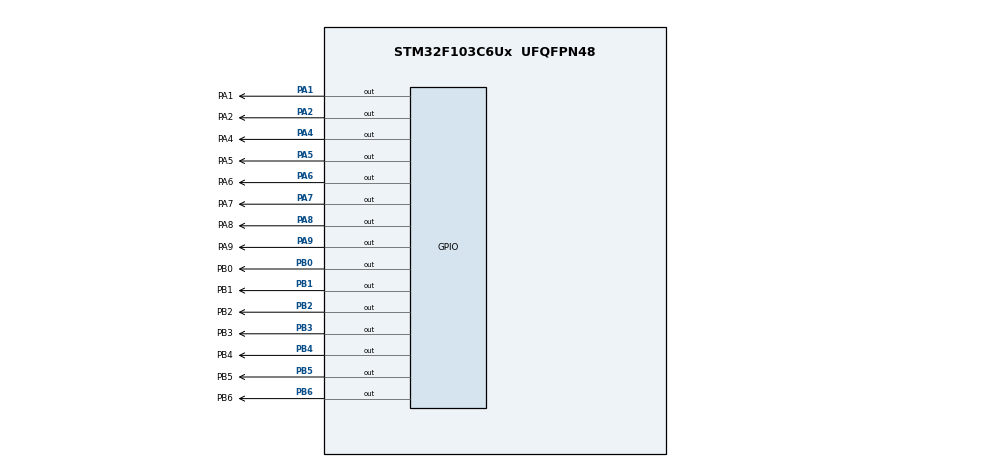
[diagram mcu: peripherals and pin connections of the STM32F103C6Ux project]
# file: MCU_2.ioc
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Mcu.Family=STM32F1
Mcu.Name=STM32F103C6Ux
Mcu.Package=UFQFPN48
NVIC.PriorityGroup=NVIC_PRIORITYGROUP_4
NVIC.TIM2_IRQn=true\:0\:0\:false\:false\:true\:true\:true\:true
PA1.GPIO_Label=PA1
PA1.Signal=GPIO_Output
PA13.Mode=Serial_Wire
PA13.Signal=SYS_JTMS-SWDIO
PA14.Mode=Serial_Wire
PA14.Signal=SYS_JTCK-SWCLK
PA2.GPIO_Label=PA2
PA2.Signal=GPIO_Output
PA4.GPIO_Label=PA4
PA4.Signal=GPIO_Output
PA5.GPIO_Label=PA5
PA5.Signal=GPIO_Output
PA6.GPIO_Label=PA6
PA6.Signal=GPIO_Output
PA7.GPIO_Label=PA7
PA7.Signal=GPIO_Output
PA8.GPIO_Label=PA8
PA8.Signal=GPIO_Output
PA9.GPIO_Label=PA9
PA9.Signal=GPIO_Output
PB0.GPIO_Label=PB0
PB0.Signal=GPIO_Output
PB1.GPIO_Label=PB1
PB1.Signal=GPIO_Output
PB2.GPIO_Label=PB2
PB2.Signal=GPIO_Output
PB3.GPIO_Label=PB3
PB3.Signal=GPIO_Output
PB4.GPIO_Label=PB4
PB4.Signal=GPIO_Output
PB5.GPIO_Label=PB5
PB5.Signal=GPIO_Output
PB6.GPIO_Label=PB6
PB6.Signal=GPIO_Output
ProjectManager.HeapSize=0x200
ProjectManager.StackSize=0x400
ProjectManager.TargetToolchain=STM32CubeIDE
RCC.APB1Freq_Value=8000000
RCC.APB2Freq_Value=8000000
TIM2.Period=9
TIM2.Prescaler=7999
VP_TIM2_VS_ClockSourceINT.Mode=Internal
board=custom

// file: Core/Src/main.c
/* USER CODE BEGIN Header */
/**
  ******************************************************************************
  * @file           : main.c
  * @brief          : Main program body
  ******************************************************************************
  * @attention
  *
  * Copyright (c) 2023 STMicroelectronics.
  * All rights reserved.
  *
  * This software is licensed under terms that can be found in the LICENSE file
  * in the root directory of this software component.
  * If no LICENSE file comes with this software, it is provided AS-IS.
  *
  ******************************************************************************
  */
/* USER CODE END Header */
#include "main.h"

/* USER CODE BEGIN Includes */
#include "software_timer.h"

/* USER CODE END Includes */

TIM_HandleTypeDef htim2;

void SystemClock_Config(void);
static void MX_GPIO_Init(void);
static void MX_TIM2_Init(void);

/* USER CODE BEGIN 0 */
void Ex_Init(){
	HAL_GPIO_WritePin(GPIOA, PA1_Pin|PA2_Pin|PA3_Pin| PA4_Pin|PA5_Pin| PA6_Pin, SET);
    HAL_GPIO_WritePin(GPIOB, PB8_Pin|PB9_Pin|PB10_Pin|PB11_Pin|PB12_Pin|PB13_Pin|PB14_Pin|PB15_Pin, SET);
    HAL_GPIO_WritePin(GPIOA, PA8_Pin|PA9_Pin|PA10_Pin|PA11_Pin|PA12_Pin|PA13_Pin|PA14_Pin|PA15_Pin, SET);
}

uint16_t row_pin[8] = {PB8_Pin,PB9_Pin,PB10_Pin,PB11_Pin,PB12_Pin,PB13_Pin,PB14_Pin,PB15_Pin};
uint16_t col_pin[8] = {PA8_Pin,PA9_Pin,PA10_Pin,PA11_Pin,PA12_Pin,PA13_Pin,PA14_Pin,PA15_Pin};
const int MAX_LED_MATRIX = 8;
int index_led_matrix = 0;
uint8_t matrix_buffer[8] = {0x1F, 0x24, 0x44, 0xC4, 0xC4, 0x44, 0x24, 0x1F};

void updateLEDMatrix(int index) {
	HAL_GPIO_WritePin(GPIOB, PB8_Pin|PB9_Pin|PB10_Pin|PB11_Pin|PB12_Pin|PB13_Pin|PB14_Pin|PB15_Pin, SET);
	HAL_GPIO_WritePin(GPIOA, PA8_Pin|PA9_Pin|PA10_Pin|PA11_Pin|PA12_Pin|PA13_Pin|PA14_Pin|PA15_Pin, SET);
	for(int j = 0; j < 100; j++){
		for(int i = 0; i < 8; i++) {
			if(matrix_buffer[index] & (0x01 << i)) {
				HAL_GPIO_WritePin(GPIOB, row_pin[i], RESET);
			}
		}

		HAL_GPIO_WritePin(GPIOA, col_pin[index], RESET);
	}

}

void display7SEG(int num){
  	uint8_t signal[10] = {0xC0, 0xF9, 0xA4, 0xB0, 0x99, 0x12, 0x82, 0xF8, 0x80, 0x90};
  	for(int i = 0; i < 7; i++ ){
  		HAL_GPIO_WritePin(PB0_GPIO_Port, PB0_Pin << i, (signal[num] >> i) & 0x01);
  	}
}
void clearAll(){
	HAL_GPIO_WritePin(GPIOA, PA3_Pin| PA4_Pin|PA5_Pin| PA6_Pin, SET);
	HAL_GPIO_WritePin(GPIOB, PB0_Pin |PB1_Pin|PB2_Pin|PB3_Pin|PB4_Pin|
			PB5_Pin|PB6_Pin,SET);
}

const int MAX_LED = 4;
int index_led = 0;
int led_buffer[4];
void update7SEG ( int index ){
	clearAll();
	switch(index){
	case 0:
		HAL_GPIO_WritePin(PA3_GPIO_Port, PA3_Pin, RESET);
		HAL_GPIO_WritePin(PA4_GPIO_Port, PA4_Pin, SET);
		HAL_GPIO_WritePin(PA5_GPIO_Port, PA5_Pin, SET);
		HAL_GPIO_WritePin(PA6_GPIO_Port, PA6_Pin, SET);
		display7SEG(led_buffer[index]);
		break;
	case 1:
		HAL_GPIO_WritePin(PA3_GPIO_Port, PA3_Pin, SET);
		HAL_GPIO_WritePin(PA4_GPIO_Port, PA4_Pin, RESET);
		HAL_GPIO_WritePin(PA5_GPIO_Port, PA5_Pin, SET);
		HAL_GPIO_WritePin(PA6_GPIO_Port, PA6_Pin, SET);
		display7SEG(led_buffer[index]);
		break;
	case 2:
		HAL_GPIO_WritePin(PA3_GPIO_Port, PA3_Pin, SET);
		HAL_GPIO_WritePin(PA4_GPIO_Port, PA4_Pin, SET);
		HAL_GPIO_WritePin(PA5_GPIO_Port, PA5_Pin, RESET);
		HAL_GPIO_WritePin(PA6_GPIO_Port, PA6_Pin, SET);
		display7SEG(led_buffer[index]);
		break;
	default:
		HAL_GPIO_WritePin(PA3_GPIO_Port, PA3_Pin, SET);
		HAL_GPIO_WritePin(PA4_GPIO_Port, PA4_Pin, SET);
		HAL_GPIO_WritePin(PA5_GPIO_Port, PA5_Pin, SET);
		HAL_GPIO_WritePin(PA6_GPIO_Port, PA6_Pin, RESET);
		display7SEG(led_buffer[index]);
		break;
	}
}
void updateClockBuffer(int hours, int minutes){
	led_buffer[0] = (hours > 9)? hours/10 : 0;
	led_buffer[1] = hours%10;
	led_buffer[2] = (minutes > 9)? minutes/10 : 0;
	led_buffer[3] = minutes%10;
}

/* USER CODE END 0 */

int main(void)
{

  /* MCU Configuration--------------------------------------------------------*/

  /* Reset of all peripherals, Initializes the Flash interface and the Systick. */
  HAL_Init();

  /* Configure the system clock */
  SystemClock_Config();

  /* Initialize all configured peripherals */
  MX_GPIO_Init();
  MX_TIM2_Init();
  /* USER CODE BEGIN 2 */
  HAL_TIM_Base_Start_IT(&htim2);
  /* USER CODE END 2 */

  /* Infinite loop */
  /* USER CODE BEGIN WHILE */
  Ex_Init();
  setTimer0(10);
  setTimer1(15);
  setTimer2(15);
  setTimer3(100);
  int hour = 15 , minute = 8 , second = 50;

  while (1)
  {
    /* USER CODE END WHILE */

    /* USER CODE BEGIN 3 */
	  if(timer0_flag == 1){
		  if(second >= 60){
			  second = 0;
			  minute++;
		  }
		  if(minute >= 60){
			  minute = 0;
			  hour++;
		  }
		  if(hour >= 24){
			  hour = 0;
		  }
		  second++;
		  updateClockBuffer(hour, minute);
		  setTimer0(100);
	  }
	  if(timer2_flag == 1){
		  update7SEG(index_led);
		  if(index_led >= 3){
			  index_led = 0;
		  }
		  else{
			 index_led++;
		  }
		  setTimer2(10);
	  }
	  if(timer1_flag == 1){
		  HAL_GPIO_TogglePin(PA1_GPIO_Port, PA1_Pin);
		  HAL_GPIO_TogglePin(PA2_GPIO_Port, PA2_Pin);
		  setTimer1(100);
	  }
	  if(timer3_flag == 1) {
		  updateLEDMatrix(index_led_matrix++);
		  if(index_led_matrix == MAX_LED_MATRIX) {
			  index_led_matrix = 0;
		  }
		  setTimer3(15);
	  }

  }
  /* USER CODE END 3 */
}

void SystemClock_Config(void)
{
  RCC_OscInitTypeDef RCC_OscInitStruct = {0};
  RCC_ClkInitTypeDef RCC_ClkInitStruct = {0};

  /** Initializes the RCC Oscillators according to the specified parameters
  * in the RCC_OscInitTypeDef structure.
  */
  RCC_OscInitStruct.OscillatorType = RCC_OSCILLATORTYPE_HSI;
  RCC_OscInitStruct.HSIState = RCC_HSI_ON;
  RCC_OscInitStruct.HSICalibrationValue = RCC_HSICALIBRATION_DEFAULT;
  RCC_OscInitStruct.PLL.PLLState = RCC_PLL_NONE;
  if (HAL_RCC_OscConfig(&RCC_OscInitStruct) != HAL_OK)
  {
    Error_Handler();
  }

  /** Initializes the CPU, AHB and APB buses clocks
  */
  RCC_ClkInitStruct.ClockType = RCC_CLOCKTYPE_HCLK|RCC_CLOCKTYPE_SYSCLK
                              |RCC_CLOCKTYPE_PCLK1|RCC_CLOCKTYPE_PCLK2;
  RCC_ClkInitStruct.SYSCLKSource = RCC_SYSCLKSOURCE_HSI;
  RCC_ClkInitStruct.AHBCLKDivider = RCC_SYSCLK_DIV1;
  RCC_ClkInitStruct.APB1CLKDivider = RCC_HCLK_DIV1;
  RCC_ClkInitStruct.APB2CLKDivider = RCC_HCLK_DIV1;

  if (HAL_RCC_ClockConfig(&RCC_ClkInitStruct, FLASH_LATENCY_0) != HAL_OK)
  {
    Error_Handler();
  }
}

static void MX_TIM2_Init(void)
{

  TIM_ClockConfigTypeDef sClockSourceConfig = {0};
  TIM_MasterConfigTypeDef sMasterConfig = {0};

  htim2.Instance = TIM2;
  htim2.Init.Prescaler = 7999;
  htim2.Init.CounterMode = TIM_COUNTERMODE_UP;
  htim2.Init.Period = 9;
  htim2.Init.ClockDivision = TIM_CLOCKDIVISION_DIV1;
  htim2.Init.AutoReloadPreload = TIM_AUTORELOAD_PRELOAD_DISABLE;
  if (HAL_TIM_Base_Init(&htim2) != HAL_OK)
  {
    Error_Handler();
  }
  sClockSourceConfig.ClockSource = TIM_CLOCKSOURCE_INTERNAL;
  if (HAL_TIM_ConfigClockSource(&htim2, &sClockSourceConfig) != HAL_OK)
  {
    Error_Handler();
  }
  sMasterConfig.MasterOutputTrigger = TIM_TRGO_RESET;
  sMasterConfig.MasterSlaveMode = TIM_MASTERSLAVEMODE_DISABLE;
  if (HAL_TIMEx_MasterConfigSynchronization(&htim2, &sMasterConfig) != HAL_OK)
  {
    Error_Handler();
  }

}

static void MX_GPIO_Init(void)
{
  GPIO_InitTypeDef GPIO_InitStruct = {0};

  /* GPIO Ports Clock Enable */
  __HAL_RCC_GPIOA_CLK_ENABLE();
  __HAL_RCC_GPIOB_CLK_ENABLE();

  /*Configure GPIO pin Output Level */
  HAL_GPIO_WritePin(GPIOA, PA1_Pin|PA2_Pin|PA3_Pin|PA4_Pin
                          |PA5_Pin|PA6_Pin|PA7_Pin|PA8_Pin
                          |PA9_Pin|PA10_Pin|PA11_Pin|PA12_Pin
                          |PA13_Pin|PA14_Pin|PA15_Pin, GPIO_PIN_RESET);

  /*Configure GPIO pin Output Level */
  HAL_GPIO_WritePin(GPIOB, PB0_Pin|PB1_Pin|PB2_Pin|PB10_Pin
                          |PB11_Pin|PB12_Pin|PB13_Pin|PB14_Pin
                          |PB15_Pin|PB3_Pin|PB4_Pin|PB5_Pin
                          |PB6_Pin|PB7_Pin|PB8_Pin|PB9_Pin, GPIO_PIN_RESET);

  /*Configure GPIO pins : PA1_Pin PA2_Pin PA3_Pin PA4_Pin
                           PA5_Pin PA6_Pin PA7_Pin PA8_Pin
                           PA9_Pin PA10_Pin PA11_Pin PA12_Pin
                           PA13_Pin PA14_Pin PA15_Pin */
  GPIO_InitStruct.Pin = PA1_Pin|PA2_Pin|PA3_Pin|PA4_Pin
                          |PA5_Pin|PA6_Pin|PA7_Pin|PA8_Pin
                          |PA9_Pin|PA10_Pin|PA11_Pin|PA12_Pin
                          |PA13_Pin|PA14_Pin|PA15_Pin;
  GPIO_InitStruct.Mode = GPIO_MODE_OUTPUT_PP;
  GPIO_InitStruct.Pull = GPIO_NOPULL;
  GPIO_InitStruct.Speed = GPIO_SPEED_FREQ_LOW;
  HAL_GPIO_Init(GPIOA, &GPIO_InitStruct);

  /*Configure GPIO pins : PB0_Pin PB1_Pin PB2_Pin PB10_Pin
                           PB11_Pin PB12_Pin PB13_Pin PB14_Pin
                           PB15_Pin PB3_Pin PB4_Pin PB5_Pin
                           PB6_Pin PB7_Pin PB8_Pin PB9_Pin */
  GPIO_InitStruct.Pin = PB0_Pin|PB1_Pin|PB2_Pin|PB10_Pin
                          |PB11_Pin|PB12_Pin|PB13_Pin|PB14_Pin
                          |PB15_Pin|PB3_Pin|PB4_Pin|PB5_Pin
                          |PB6_Pin|PB7_Pin|PB8_Pin|PB9_Pin;
  GPIO_InitStruct.Mode = GPIO_MODE_OUTPUT_PP;
  GPIO_InitStruct.Pull = GPIO_NOPULL;
  GPIO_InitStruct.Speed = GPIO_SPEED_FREQ_LOW;
  HAL_GPIO_Init(GPIOB, &GPIO_InitStruct);

}

/* USER CODE BEGIN 4 */
void HAL_TIM_PeriodElapsedCallback (TIM_HandleTypeDef *htim ){
	timerRun();
}

/* USER CODE END 4 */

void Error_Handler(void)
{
  __disable_irq();
  while (1)
  {
  }
}
